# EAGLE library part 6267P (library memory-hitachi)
MEMORY

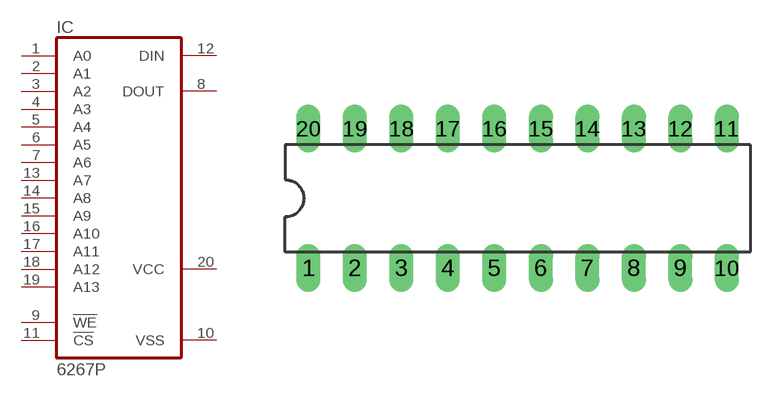
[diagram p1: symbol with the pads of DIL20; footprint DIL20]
Designator prefix IC

## 6267P (OC_FARNELL: unknown; OC_NEWARK: unknown)  [DIL20]
1  A0  in
2  A1  in
3  A2  in
4  A3  in
5  A4  in
6  A5  in
7  A6  in
8  DOUT  hiz
9  !WE  in
10  VSS  pwr
11  !CS  in
12  DIN  in
13  A7  in
14  A8  in
15  A9  in
16  A10  in
17  A11  in
18  A12  in
19  A13  in
20  VCC  pwr

## Footprint DIL20 (pad centres in mm)
Dual In Line Package
drill 0.813 long: 1 -11.43,-3.81; 2 -8.89,-3.81; 3 -6.35,-3.81; 4 -3.81,-3.81; 5 -1.27,-3.81; 6 1.27,-3.81; 7 3.81,-3.81; 8 6.35,-3.81; 9 8.89,-3.81; 10 11.43,-3.81; 11 11.43,3.81; 12 8.89,3.81; 13 6.35,3.81; 14 3.81,3.81; 15 1.27,3.81; 16 -1.27,3.81; 17 -3.81,3.81; 18 -6.35,3.81; 19 -8.89,3.81; 20 -11.43,3.81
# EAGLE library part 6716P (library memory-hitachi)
MEMORY

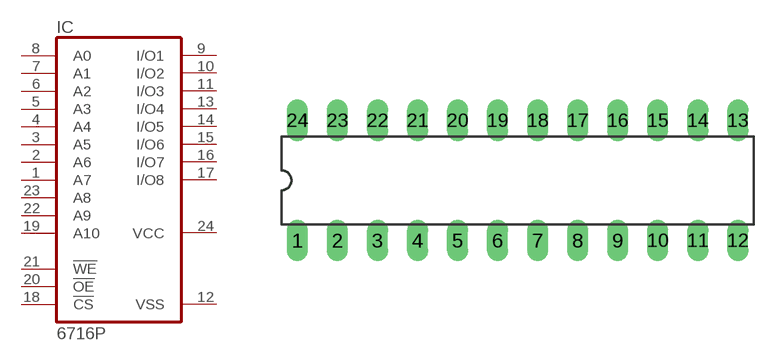
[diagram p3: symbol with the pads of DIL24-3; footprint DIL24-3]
Designator prefix IC

## 6716P (OC_FARNELL: unknown; OC_NEWARK: unknown)  [DIL24-3]
1  A7  in
2  A6  in
3  A5  in
4  A4  in
5  A3  in
6  A2  in
7  A1  in
8  A0  in
9  I/O1
10  I/O2
11  I/O3
12  VSS  pwr
13  I/O4
14  I/O5
15  I/O6
16  I/O7
17  I/O8
18  !CS  in
19  A10  in
20  !OE  in
21  !WE  in
22  A9  in
23  A8  in
24  VCC  pwr

## Footprint DIL24-3 (pad centres in mm)
Dual In Line Package 0.3 inch
drill 0.813 long: 1 -13.97,-3.81; 2 -11.43,-3.81; 3 -8.89,-3.81; 4 -6.35,-3.81; 5 -3.81,-3.81; 6 -1.27,-3.81; 7 1.27,-3.81; 8 3.81,-3.81; 9 6.35,-3.81; 10 8.89,-3.81; 11 11.43,-3.81; 12 13.97,-3.81; 13 13.97,3.81; 14 11.43,3.81; 15 8.89,3.81; 16 6.35,3.81; 17 3.81,3.81; 18 1.27,3.81; 19 -1.27,3.81; 20 -3.81,3.81; 21 -6.35,3.81; 22 -8.89,3.81; 23 -11.43,3.81; 24 -13.97,3.81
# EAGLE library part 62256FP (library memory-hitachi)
MEMORY

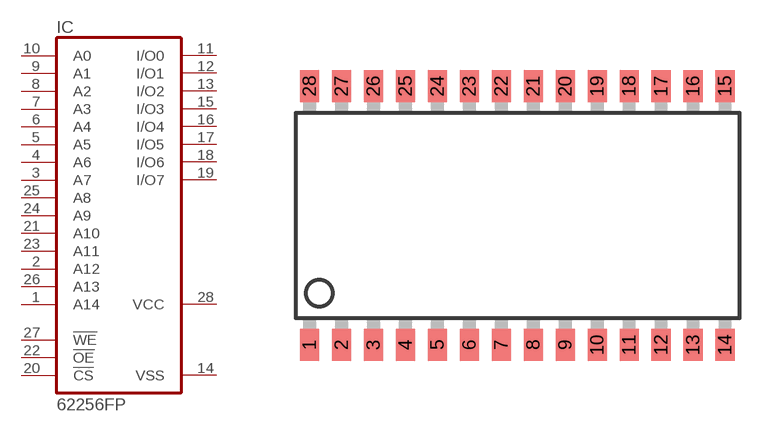
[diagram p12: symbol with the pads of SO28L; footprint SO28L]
Designator prefix IC

## 62256FP (MPN: CY62256VNLL-70SNXI; OC_FARNELL: 1650073; OC_NEWARK: 19M2582)  [SO28L]
1  A14  in
2  A12  in
3  A7  in
4  A6  in
5  A5  in
6  A4  in
7  A3  in
8  A2  in
9  A1  in
10  A0  in
11  I/O0
12  I/O1
13  I/O2
14  VSS  pwr
15  I/O3
16  I/O4
17  I/O5
18  I/O6
19  I/O7
20  !CS  in
21  A10  in
22  !OE  in
23  A11  in
24  A9  in
25  A8  in
26  A13  in
27  !WE  in
28  VCC  pwr

## Footprint SO28L (pad centres in mm)
Small Outline large
smd 0.762 x 1.27: 1 -7.62,-5.207; 2 -6.35,-5.207; 3 -5.08,-5.207; 4 -3.81,-5.207; 5 -2.54,-5.207; 6 -1.27,-5.207; 7 0,-5.207; 8 1.27,-5.207; 9 2.54,-5.207; 10 3.81,-5.207; 11 5.08,-5.207; 12 6.35,-5.207; 13 7.62,-5.207; 14 8.89,-5.207; 15 8.89,5.08; 16 7.62,5.08; 17 6.35,5.08; 18 5.08,5.08; 19 3.81,5.08; 20 2.54,5.08; 21 1.27,5.08; 22 0,5.08; 23 -1.27,5.08; 24 -2.54,5.08; 25 -3.81,5.08; 26 -5.08,5.08; 27 -6.35,5.08; 28 -7.62,5.08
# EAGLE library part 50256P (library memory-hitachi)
MEMORY

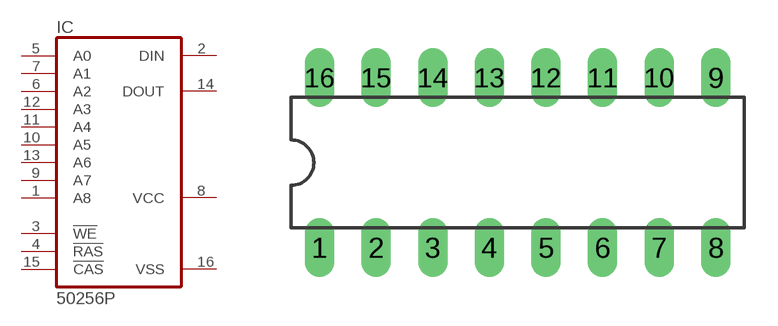
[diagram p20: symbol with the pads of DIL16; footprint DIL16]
Designator prefix IC

## 50256P (OC_FARNELL: unknown; OC_NEWARK: unknown)  [DIL16]
1  A8  in
2  DIN  in
3  !WE  in
4  !RAS  in
5  A0  in
6  A2  in
7  A1  in
8  VCC  pwr
9  A7  in
10  A5  in
11  A4  in
12  A3  in
13  A6  in
14  DOUT  hiz
15  !CAS  in
16  VSS  pwr

## Footprint DIL16 (pad centres in mm)
Dual In Line Package
drill 0.813 long: 1 -8.89,-3.81; 2 -6.35,-3.81; 3 -3.81,-3.81; 4 -1.27,-3.81; 5 1.27,-3.81; 6 3.81,-3.81; 7 6.35,-3.81; 8 8.89,-3.81; 9 8.89,3.81; 10 6.35,3.81; 11 3.81,3.81; 12 1.27,3.81; 13 -1.27,3.81; 14 -3.81,3.81; 15 -6.35,3.81; 16 -8.89,3.81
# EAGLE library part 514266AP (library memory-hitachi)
MEMORY

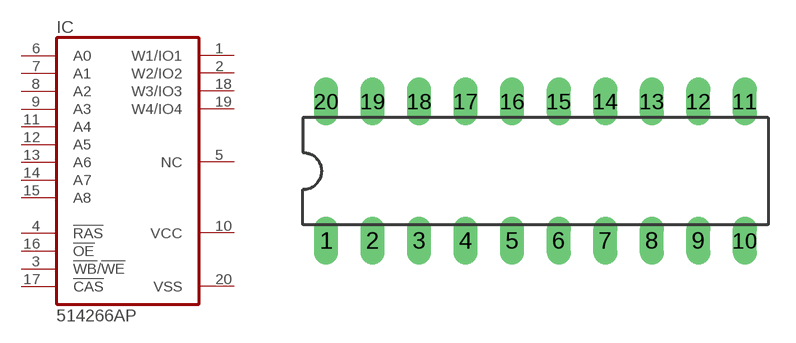
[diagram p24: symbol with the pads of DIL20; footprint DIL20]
Designator prefix IC

## 514266AP (OC_FARNELL: unknown; OC_NEWARK: unknown)  [DIL20]
1  W1/IO1
2  W2/IO2
3  !WB!/!WE  in
4  !RAS  in
5  NC  nc
6  A0  in
7  A1  in
8  A2  in
9  A3  in
10  VCC  pwr
11  A4  in
12  A5  in
13  A6  in
14  A7  in
15  A8  in
16  !OE  in
17  !CAS  in
18  W3/IO3
19  W4/IO4
20  VSS  pwr

## Footprint DIL20 (pad centres in mm)
Dual In Line Package
drill 0.813 long: 1 -11.43,-3.81; 2 -8.89,-3.81; 3 -6.35,-3.81; 4 -3.81,-3.81; 5 -1.27,-3.81; 6 1.27,-3.81; 7 3.81,-3.81; 8 6.35,-3.81; 9 8.89,-3.81; 10 11.43,-3.81; 11 11.43,3.81; 12 8.89,3.81; 13 6.35,3.81; 14 3.81,3.81; 15 1.27,3.81; 16 -1.27,3.81; 17 -3.81,3.81; 18 -6.35,3.81; 19 -8.89,3.81; 20 -11.43,3.81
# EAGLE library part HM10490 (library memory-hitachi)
MEMORY

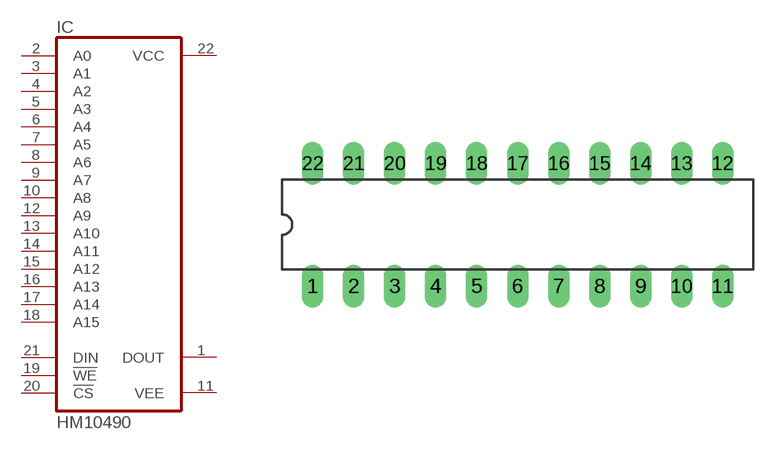
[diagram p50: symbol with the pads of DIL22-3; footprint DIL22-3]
Designator prefix IC

## HM10490 (OC_FARNELL: unknown; OC_NEWARK: unknown)  [DIL22-3]
1  DOUT  hiz
2  A0  in
3  A1  in
4  A2  in
5  A3  in
6  A4  in
7  A5  in
8  A6  in
9  A7  in
10  A8  in
11  VEE  pwr
12  A9  in
13  A10  in
14  A11  in
15  A12  in
16  A13  in
17  A14  in
18  A15  in
19  !WE  in
20  !CS  in
21  DIN  in
22  VCC  pwr

## Footprint DIL22-3 (pad centres in mm)
Dual In Line Package 0.3 inch
drill 0.813 long: 1 -12.7,-3.81; 2 -10.16,-3.81; 3 -7.62,-3.81; 4 -5.08,-3.81; 5 -2.54,-3.81; 6 0,-3.81; 7 2.54,-3.81; 8 5.08,-3.81; 9 7.62,-3.81; 10 10.16,-3.81; 11 12.7,-3.81; 12 12.7,3.81; 13 10.16,3.81; 14 7.62,3.81; 15 5.08,3.81; 16 2.54,3.81; 17 0,3.81; 18 -2.54,3.81; 19 -5.08,3.81; 20 -7.62,3.81; 21 -10.16,3.81; 22 -12.7,3.81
